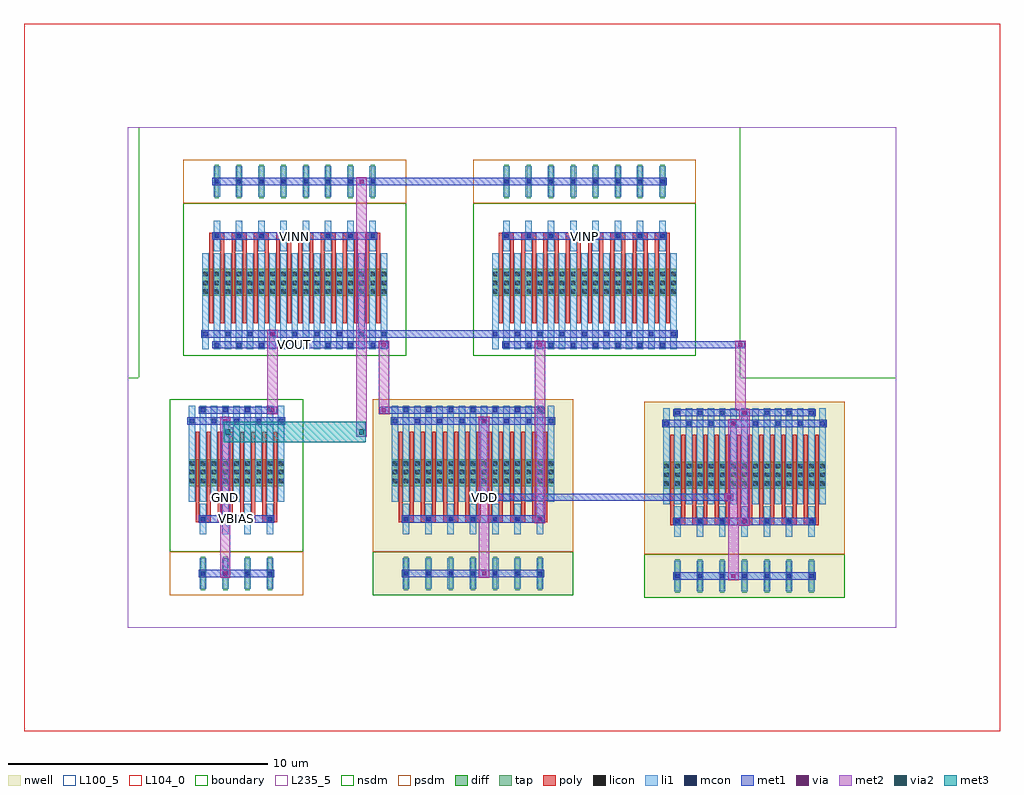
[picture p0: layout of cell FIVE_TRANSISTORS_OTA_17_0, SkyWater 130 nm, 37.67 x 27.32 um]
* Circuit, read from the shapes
.subckt FIVE_TRANSISTORS_OTA_17_0 GND VBIAS VDD VINN VINP VOUT
XM1 n1 VBIAS GND GND sky130_fd_pr__nfet_01v8 w=1.05 l=0.15 m=8
XM2 VOUT VINN n1 GND sky130_fd_pr__nfet_01v8 w=1.05 l=0.15 m=16
XM3 n2 VINP n1 GND sky130_fd_pr__nfet_01v8 w=1.05 l=0.15 m=16
XM4 VOUT n2 VDD VDD sky130_fd_pr__pfet_01v8 w=1.05 l=0.15 m=14
XM5 n2 n2 VDD VDD sky130_fd_pr__pfet_01v8 w=1.05 l=0.15 m=14
.ends

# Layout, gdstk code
from math import pi, radians
import gdstk
lib = gdstk.Library(unit=1e-6, precision=1e-09)
def R(c, l, rs):  # rectangles x0, y0, x1, y1
    for r in rs: c.add(gdstk.rectangle(r[:2], r[2:], *l))
def A(c, l, x, y, w, h, nx, ny, dx, dy):  # array of equal rectangles
    R(c, l, [(x+i*dx, y+j*dy, x+i*dx+w, y+j*dy+h) for i in range(nx) for j in range(ny)])
def P(c, l, *ps):  # polygons
    for p in ps: c.add(gdstk.Polygon(p, *l))
nwell = (64, 20)
diff = (65, 20)
tap = (65, 44)
poly = (66, 20)
licon = (66, 44)
li1 = (67, 20)
mcon = (67, 44)
met1 = (68, 20)
via = (68, 44)
met2 = (69, 20)
via2 = (69, 44)
met3 = (70, 20)
nsdm = (93, 44)
psdm = (94, 20)
L100_5 = (100, 5)
L104_0 = (104, 0)
boundary = (235, 4)
L235_5 = (235, 5)

dcl_pmos_s_28041393_x7_y = lib.new_cell('DCL_PMOS_S_28041393_X7_Y1_1746771636')
R(dcl_pmos_s_28041393_x7_y, nwell, [(1.99,0.94,9.73,8.5)])
R(dcl_pmos_s_28041393_x7_y, diff, [(2.725,3.25,8.995,4.3)])
A(dcl_pmos_s_28041393_x7_y, tap, 3.195, 7.015, 0.17, 1.29, 7, 1, 0.86, 0)
A(dcl_pmos_s_28041393_x7_y, poly, 2.99, 2.2, 0.15, 3.36, 14, 1, 0.43, 0)
A(dcl_pmos_s_28041393_x7_y, poly, 2.99, 5.425, 0.58, 0.27, 7, 1, 0.86, 0)
A(dcl_pmos_s_28041393_x7_y, licon, 2.765, 3.33, 0.17, 0.17, 3, 3, 0.43, 0.34)
A(dcl_pmos_s_28041393_x7_y, licon, 3.625, 3.33, 0.17, 0.17, 3, 3, 0.43, 0.34)
A(dcl_pmos_s_28041393_x7_y, licon, 4.485, 3.33, 0.17, 0.17, 3, 3, 0.43, 0.34)
A(dcl_pmos_s_28041393_x7_y, licon, 5.345, 3.33, 0.17, 0.17, 3, 3, 0.43, 0.34)
A(dcl_pmos_s_28041393_x7_y, licon, 6.205, 3.33, 0.17, 0.17, 3, 3, 0.43, 0.34)
A(dcl_pmos_s_28041393_x7_y, licon, 7.065, 3.33, 0.17, 0.17, 3, 3, 0.43, 0.34)
A(dcl_pmos_s_28041393_x7_y, licon, 7.925, 3.33, 0.17, 0.17, 3, 3, 0.43, 0.34)
A(dcl_pmos_s_28041393_x7_y, licon, 3.195, 5.475, 0.17, 0.17, 7, 2, 0.86, 2.1)
A(dcl_pmos_s_28041393_x7_y, li1, 2.725, 1.19, 0.25, 3.7, 15, 1, 0.43, 0)
A(dcl_pmos_s_28041393_x7_y, li1, 3.155, 4.97, 0.25, 1.18, 7, 2, 0.86, 2.1)
A(dcl_pmos_s_28041393_x7_y, mcon, 3.195, 1.275, 0.17, 0.17, 7, 2, 0.86, 4.2)
A(dcl_pmos_s_28041393_x7_y, mcon, 2.765, 1.695, 0.17, 0.17, 8, 1, 0.86, 0)
A(dcl_pmos_s_28041393_x7_y, mcon, 3.195, 7.575, 0.17, 0.17, 7, 1, 0.86, 0)
R(dcl_pmos_s_28041393_x7_y, met1, [(3.11,1.22,8.61,1.5), (2.68,1.64,9.04,1.92), (3.11,5.42,8.61,5.7), (3.11,7.52,8.61,7.8)])
R(dcl_pmos_s_28041393_x7_y, via, [(5.785,1.285,5.935,1.435), (6.215,1.705,6.365,1.855), (5.785,5.485,5.935,5.635), (6.215,7.585,6.365,7.735)])
R(dcl_pmos_s_28041393_x7_y, met2, [(5.66,1.2,6.06,5.72), (6.09,1.62,6.49,7.82)])
R(dcl_pmos_s_28041393_x7_y, nsdm, [(1.99,6.82,9.73,8.5)])
R(dcl_pmos_s_28041393_x7_y, psdm, [(1.99,0.94,9.73,6.82)])
R(dcl_pmos_s_28041393_x7_y, L100_5, [(0,0,10.75,9.66)])
R(dcl_pmos_s_28041393_x7_y, boundary, [(0,0,10.75,9.66)])

nmos_s_67517085_x4_y1_17 = lib.new_cell('NMOS_S_67517085_X4_Y1_1746771639')
R(nmos_s_67517085_x4_y1_17, diff, [(2.125,3.15,5.815,4.2)])
A(nmos_s_67517085_x4_y1_17, tap, 2.595, 6.915, 0.17, 1.29, 4, 1, 0.86, 0)
A(nmos_s_67517085_x4_y1_17, poly, 2.39, 2.1, 0.15, 3.36, 8, 1, 0.43, 0)
A(nmos_s_67517085_x4_y1_17, poly, 2.39, 5.325, 0.58, 0.27, 4, 1, 0.86, 0)
A(nmos_s_67517085_x4_y1_17, licon, 2.165, 3.23, 0.17, 0.17, 3, 3, 0.43, 0.34)
A(nmos_s_67517085_x4_y1_17, licon, 3.025, 3.23, 0.17, 0.17, 3, 3, 0.43, 0.34)
A(nmos_s_67517085_x4_y1_17, licon, 3.885, 3.23, 0.17, 0.17, 3, 3, 0.43, 0.34)
A(nmos_s_67517085_x4_y1_17, licon, 4.745, 3.23, 0.17, 0.17, 3, 3, 0.43, 0.34)
A(nmos_s_67517085_x4_y1_17, licon, 2.595, 5.375, 0.17, 0.17, 4, 2, 0.86, 2.1)
A(nmos_s_67517085_x4_y1_17, li1, 2.125, 1.09, 0.25, 3.7, 9, 1, 0.43, 0)
A(nmos_s_67517085_x4_y1_17, li1, 2.555, 4.87, 0.25, 1.18, 4, 2, 0.86, 2.1)
A(nmos_s_67517085_x4_y1_17, mcon, 2.595, 1.175, 0.17, 0.17, 4, 2, 0.86, 4.2)
A(nmos_s_67517085_x4_y1_17, mcon, 2.165, 1.595, 0.17, 0.17, 5, 1, 0.86, 0)
A(nmos_s_67517085_x4_y1_17, mcon, 2.595, 7.475, 0.17, 0.17, 4, 1, 0.86, 0)
R(nmos_s_67517085_x4_y1_17, met1, [(2.51,1.12,5.43,1.4), (2.08,1.54,5.86,1.82), (2.51,5.32,5.43,5.6), (2.51,7.42,5.43,7.7)])
R(nmos_s_67517085_x4_y1_17, via, [(4.325,1.605,4.475,1.755), (4.325,7.485,4.475,7.635)])
R(nmos_s_67517085_x4_y1_17, met2, [(4.2,1.52,4.6,7.72)])
R(nmos_s_67517085_x4_y1_17, nsdm, [(1.39,0.84,6.55,6.72)])
R(nmos_s_67517085_x4_y1_17, psdm, [(1.39,6.72,6.55,8.4)])
R(nmos_s_67517085_x4_y1_17, L100_5, [(0,0,8.17,9.66)])
R(nmos_s_67517085_x4_y1_17, boundary, [(0,0,8.17,9.66)])

pmos_s_48447827_x7_y1_17 = lib.new_cell('PMOS_S_48447827_X7_Y1_1746771640')
R(pmos_s_48447827_x7_y1_17, nwell, [(1.29,0.84,9.03,8.4)])
R(pmos_s_48447827_x7_y1_17, diff, [(2.025,3.15,8.295,4.2)])
A(pmos_s_48447827_x7_y1_17, tap, 2.495, 6.915, 0.17, 1.29, 7, 1, 0.86, 0)
A(pmos_s_48447827_x7_y1_17, poly, 2.29, 2.1, 0.15, 3.36, 14, 1, 0.43, 0)
A(pmos_s_48447827_x7_y1_17, poly, 2.29, 5.325, 0.58, 0.27, 7, 1, 0.86, 0)
A(pmos_s_48447827_x7_y1_17, licon, 2.065, 3.23, 0.17, 0.17, 3, 3, 0.43, 0.34)
A(pmos_s_48447827_x7_y1_17, licon, 2.925, 3.23, 0.17, 0.17, 3, 3, 0.43, 0.34)
A(pmos_s_48447827_x7_y1_17, licon, 3.785, 3.23, 0.17, 0.17, 3, 3, 0.43, 0.34)
A(pmos_s_48447827_x7_y1_17, licon, 4.645, 3.23, 0.17, 0.17, 3, 3, 0.43, 0.34)
A(pmos_s_48447827_x7_y1_17, licon, 5.505, 3.23, 0.17, 0.17, 3, 3, 0.43, 0.34)
A(pmos_s_48447827_x7_y1_17, licon, 6.365, 3.23, 0.17, 0.17, 3, 3, 0.43, 0.34)
A(pmos_s_48447827_x7_y1_17, licon, 7.225, 3.23, 0.17, 0.17, 3, 3, 0.43, 0.34)
A(pmos_s_48447827_x7_y1_17, licon, 2.495, 5.375, 0.17, 0.17, 7, 2, 0.86, 2.1)
A(pmos_s_48447827_x7_y1_17, li1, 2.025, 1.09, 0.25, 3.7, 15, 1, 0.43, 0)
A(pmos_s_48447827_x7_y1_17, li1, 2.455, 4.87, 0.25, 1.18, 7, 2, 0.86, 2.1)
A(pmos_s_48447827_x7_y1_17, mcon, 2.495, 1.175, 0.17, 0.17, 7, 2, 0.86, 4.2)
A(pmos_s_48447827_x7_y1_17, mcon, 2.065, 1.595, 0.17, 0.17, 8, 1, 0.86, 0)
A(pmos_s_48447827_x7_y1_17, mcon, 2.495, 7.475, 0.17, 0.17, 7, 1, 0.86, 0)
R(pmos_s_48447827_x7_y1_17, met1, [(2.41,1.12,7.91,1.4), (1.98,1.54,8.34,1.82), (2.41,5.32,7.91,5.6), (2.41,7.42,7.91,7.7)])
R(pmos_s_48447827_x7_y1_17, via, [(5.515,1.605,5.665,1.755), (5.515,7.485,5.665,7.635)])
R(pmos_s_48447827_x7_y1_17, met2, [(5.39,1.52,5.79,7.72)])
R(pmos_s_48447827_x7_y1_17, nsdm, [(1.29,6.72,9.03,8.4)])
R(pmos_s_48447827_x7_y1_17, psdm, [(1.29,0.84,9.03,6.72)])
R(pmos_s_48447827_x7_y1_17, L100_5, [(0,0,10.75,9.66)])
R(pmos_s_48447827_x7_y1_17, boundary, [(0,0,10.75,9.66)])

nmos_4t_16320549_x8_y1_1 = lib.new_cell('NMOS_4T_16320549_X8_Y1_1746771637')
R(nmos_4t_16320549_x8_y1_1, diff, [(2.025,3.15,9.155,4.2)])
A(nmos_4t_16320549_x8_y1_1, tap, 2.495, 6.915, 0.17, 1.29, 8, 1, 0.86, 0)
A(nmos_4t_16320549_x8_y1_1, poly, 2.29, 2.1, 0.15, 3.36, 16, 1, 0.43, 0)
A(nmos_4t_16320549_x8_y1_1, poly, 2.29, 5.325, 0.58, 0.27, 8, 1, 0.86, 0)
A(nmos_4t_16320549_x8_y1_1, licon, 2.065, 3.23, 0.17, 0.17, 3, 3, 0.43, 0.34)
A(nmos_4t_16320549_x8_y1_1, licon, 2.925, 3.23, 0.17, 0.17, 3, 3, 0.43, 0.34)
A(nmos_4t_16320549_x8_y1_1, licon, 3.785, 3.23, 0.17, 0.17, 3, 3, 0.43, 0.34)
A(nmos_4t_16320549_x8_y1_1, licon, 4.645, 3.23, 0.17, 0.17, 3, 3, 0.43, 0.34)
A(nmos_4t_16320549_x8_y1_1, licon, 5.505, 3.23, 0.17, 0.17, 3, 3, 0.43, 0.34)
A(nmos_4t_16320549_x8_y1_1, licon, 6.365, 3.23, 0.17, 0.17, 3, 3, 0.43, 0.34)
A(nmos_4t_16320549_x8_y1_1, licon, 7.225, 3.23, 0.17, 0.17, 3, 3, 0.43, 0.34)
A(nmos_4t_16320549_x8_y1_1, licon, 8.085, 3.23, 0.17, 0.17, 3, 3, 0.43, 0.34)
A(nmos_4t_16320549_x8_y1_1, licon, 2.495, 5.375, 0.17, 0.17, 8, 2, 0.86, 2.1)
A(nmos_4t_16320549_x8_y1_1, li1, 2.025, 1.09, 0.25, 3.7, 17, 1, 0.43, 0)
A(nmos_4t_16320549_x8_y1_1, li1, 2.455, 4.87, 0.25, 1.18, 8, 2, 0.86, 2.1)
A(nmos_4t_16320549_x8_y1_1, mcon, 2.495, 1.175, 0.17, 0.17, 8, 2, 0.86, 4.2)
A(nmos_4t_16320549_x8_y1_1, mcon, 2.065, 1.595, 0.17, 0.17, 9, 1, 0.86, 0)
A(nmos_4t_16320549_x8_y1_1, mcon, 2.495, 7.475, 0.17, 0.17, 8, 1, 0.86, 0)
R(nmos_4t_16320549_x8_y1_1, met1, [(2.41,1.12,8.77,1.4), (1.98,1.54,9.2,1.82), (2.41,5.32,8.77,5.6), (2.41,7.42,8.77,7.7)])
R(nmos_4t_16320549_x8_y1_1, nsdm, [(1.29,0.84,9.89,6.72)])
R(nmos_4t_16320549_x8_y1_1, psdm, [(1.29,6.72,9.89,8.4)])
R(nmos_4t_16320549_x8_y1_1, L100_5, [(0,0,11.61,9.66)])
R(nmos_4t_16320549_x8_y1_1, boundary, [(0,0,11.61,9.66)])

nmos_4t_2405365_x8_y1_17 = lib.new_cell('NMOS_4T_2405365_X8_Y1_1746771638')
R(nmos_4t_2405365_x8_y1_17, diff, [(2.025,3.15,9.155,4.2)])
A(nmos_4t_2405365_x8_y1_17, tap, 2.495, 6.915, 0.17, 1.29, 8, 1, 0.86, 0)
A(nmos_4t_2405365_x8_y1_17, poly, 2.29, 2.1, 0.15, 3.36, 16, 1, 0.43, 0)
A(nmos_4t_2405365_x8_y1_17, poly, 2.29, 5.325, 0.58, 0.27, 8, 1, 0.86, 0)
A(nmos_4t_2405365_x8_y1_17, licon, 2.065, 3.23, 0.17, 0.17, 3, 3, 0.43, 0.34)
A(nmos_4t_2405365_x8_y1_17, licon, 2.925, 3.23, 0.17, 0.17, 3, 3, 0.43, 0.34)
A(nmos_4t_2405365_x8_y1_17, licon, 3.785, 3.23, 0.17, 0.17, 3, 3, 0.43, 0.34)
A(nmos_4t_2405365_x8_y1_17, licon, 4.645, 3.23, 0.17, 0.17, 3, 3, 0.43, 0.34)
A(nmos_4t_2405365_x8_y1_17, licon, 5.505, 3.23, 0.17, 0.17, 3, 3, 0.43, 0.34)
A(nmos_4t_2405365_x8_y1_17, licon, 6.365, 3.23, 0.17, 0.17, 3, 3, 0.43, 0.34)
A(nmos_4t_2405365_x8_y1_17, licon, 7.225, 3.23, 0.17, 0.17, 3, 3, 0.43, 0.34)
A(nmos_4t_2405365_x8_y1_17, licon, 8.085, 3.23, 0.17, 0.17, 3, 3, 0.43, 0.34)
A(nmos_4t_2405365_x8_y1_17, licon, 2.495, 5.375, 0.17, 0.17, 8, 2, 0.86, 2.1)
A(nmos_4t_2405365_x8_y1_17, li1, 2.025, 1.09, 0.25, 3.7, 17, 1, 0.43, 0)
A(nmos_4t_2405365_x8_y1_17, li1, 2.455, 4.87, 0.25, 1.18, 8, 2, 0.86, 2.1)
A(nmos_4t_2405365_x8_y1_17, mcon, 2.495, 1.175, 0.17, 0.17, 8, 2, 0.86, 4.2)
A(nmos_4t_2405365_x8_y1_17, mcon, 2.065, 1.595, 0.17, 0.17, 9, 1, 0.86, 0)
A(nmos_4t_2405365_x8_y1_17, mcon, 2.495, 7.475, 0.17, 0.17, 8, 1, 0.86, 0)
R(nmos_4t_2405365_x8_y1_17, met1, [(2.41,1.12,8.77,1.4), (1.98,1.54,9.2,1.82), (2.41,5.32,8.77,5.6), (2.41,7.42,8.77,7.7)])
R(nmos_4t_2405365_x8_y1_17, nsdm, [(1.29,0.84,9.89,6.72)])
R(nmos_4t_2405365_x8_y1_17, psdm, [(1.29,6.72,9.89,8.4)])
R(nmos_4t_2405365_x8_y1_17, L100_5, [(0,0,11.61,9.66)])
R(nmos_4t_2405365_x8_y1_17, boundary, [(0,0,11.61,9.66)])

five_transistors_ota_17_ = lib.new_cell('FIVE_TRANSISTORS_OTA_17_0')
R(five_transistors_ota_17_, met1, [(15.75,4.06,16.07,4.34), (15.75,4.06,16.07,4.34), (15.75,4.06,16.07,4.34), (15.75,4.06,16.07,4.34), (13.6,4.9,13.92,5.18), (13.6,4.9,13.92,5.18), (13.76,4.9,23.22,5.18), (23.06,4.9,23.38,5.18), (23.06,4.9,23.38,5.18), (5.43,8.26,5.75,8.54), (5.43,8.26,5.75,8.54), (5.43,8.26,5.75,8.54), (5.43,8.26,5.75,8.54), (9.73,8.26,10.05,8.54), (9.73,8.26,10.05,8.54), (9.89,8.26,10.75,8.54), (9.46,10.78,9.89,11.06), (9.73,10.78,10.05,11.06), (9.73,10.78,10.05,11.06), (15.75,10.78,16.07,11.06), (15.75,10.78,16.07,11.06), (15.75,10.78,16.07,11.06), (15.75,10.78,16.07,11.06), (20.64,10.78,23.65,11.06), (23.49,10.78,23.81,11.06), (23.49,10.78,23.81,11.06), (5.43,11.2,5.75,11.48), (5.43,11.2,5.75,11.48), (5.43,11.2,5.75,11.48), (5.43,11.2,5.75,11.48), (9.89,11.2,14.19,11.48), (8.87,17.08,9.19,17.36), (8.87,17.08,9.19,17.36), (8.87,17.08,9.19,17.36), (8.87,17.08,9.19,17.36), (9.46,17.08,14.62,17.36)])
P(five_transistors_ota_17_, met1, [(0,0),(0,0),(0,0),(0,0)],
  [(0,0),(0,0),(0,0),(0,0)],
  [(0,0),(0,0),(0,0),(0,0)],
  [(0,0),(0,0),(0,0),(0,0)],
  [(0,0),(0,0),(0,0),(0,0)],
  [(0,0),(0,0),(0,0),(0,0)],
  [(0,0),(0,0),(0,0),(0,0)],
  [(0,0),(0,0),(0,0),(0,0)],
  [(0,0),(0,0),(0,0),(0,0)],
  [(0,0),(0,0),(0,0),(0,0)],
  [(0,0),(0,0),(0,0),(0,0)],
  [(0,0),(0,0),(0,0),(0,0)],
  [(0,0),(0,0),(0,0),(0,0)],
  [(0,0),(0,0),(0,0),(0,0)],
  [(0,0),(0,0),(0,0),(0,0)],
  [(0,0),(0,0),(0,0),(0,0)])
R(five_transistors_ota_17_, via, [(15.835,4.125,15.985,4.275), (15.835,4.125,15.985,4.275), (15.835,4.125,15.985,4.275), (15.835,4.125,15.985,4.275), (13.685,4.965,13.835,5.115), (13.685,4.965,13.835,5.115), (23.145,4.965,23.295,5.115), (23.145,4.965,23.295,5.115), (5.515,8.325,5.665,8.475), (5.515,8.325,5.665,8.475), (5.515,8.325,5.665,8.475), (5.515,8.325,5.665,8.475), (9.815,8.325,9.965,8.475), (9.815,8.325,9.965,8.475), (9.815,10.845,9.965,10.995), (9.815,10.845,9.965,10.995), (15.835,10.845,15.985,10.995), (15.835,10.845,15.985,10.995), (15.835,10.845,15.985,10.995), (15.835,10.845,15.985,10.995), (23.575,10.845,23.725,10.995), (23.575,10.845,23.725,10.995), (5.515,11.265,5.665,11.415), (5.515,11.265,5.665,11.415), (5.515,11.265,5.665,11.415), (5.515,11.265,5.665,11.415), (8.955,17.145,9.105,17.295), (8.955,17.145,9.105,17.295), (8.955,17.145,9.105,17.295), (8.955,17.145,9.105,17.295)])
R(five_transistors_ota_17_, met2, [(15.71,4.04,16.11,4.36), (15.71,4.04,16.11,4.36), (15.71,4.04,16.11,4.36), (15.71,4.04,16.11,4.36), (15.71,4.2,16.11,10.92), (13.56,4.88,13.96,5.2), (13.56,4.88,13.96,5.2), (23.02,4.88,23.42,5.2), (23.02,4.88,23.42,5.2), (3.67,7.375,4.07,7.745), (3.67,7.375,4.07,7.745), (3.67,7.375,4.07,7.745), (3.67,7.375,4.07,7.745), (8.83,7.375,9.23,7.745), (8.83,7.375,9.23,7.745), (8.83,7.375,9.23,7.745), (8.83,7.375,9.23,7.745), (8.83,7.56,9.23,17.22), (5.39,8.24,5.79,8.56), (5.39,8.24,5.79,8.56), (5.39,8.24,5.79,8.56), (5.39,8.24,5.79,8.56), (9.69,8.24,10.09,8.56), (9.69,8.24,10.09,8.56), (5.39,8.4,5.79,11.34), (9.69,8.4,10.09,10.92), (23.45,8.4,23.85,10.92), (9.69,10.76,10.09,11.08), (9.69,10.76,10.09,11.08), (15.71,10.76,16.11,11.08), (15.71,10.76,16.11,11.08), (15.71,10.76,16.11,11.08), (15.71,10.76,16.11,11.08), (23.45,10.76,23.85,11.08), (23.45,10.76,23.85,11.08), (5.39,11.18,5.79,11.5), (5.39,11.18,5.79,11.5), (5.39,11.18,5.79,11.5), (5.39,11.18,5.79,11.5), (8.83,17.06,9.23,17.38), (8.83,17.06,9.23,17.38), (8.83,17.06,9.23,17.38), (8.83,17.06,9.23,17.38)])
P(five_transistors_ota_17_, met2, [(0,0),(0,0),(0,0),(0,0)],
  [(0,0),(0,0),(0,0),(0,0)],
  [(0,0),(0,0),(0,0),(0,0)],
  [(0,0),(0,0),(0,0),(0,0)],
  [(0,0),(0,0),(0,0),(0,0)],
  [(0,0),(0,0),(0,0),(0,0)])
R(five_transistors_ota_17_, via2, [(3.77,7.46,3.97,7.66), (3.77,7.46,3.97,7.66), (3.77,7.46,3.97,7.66), (3.77,7.46,3.97,7.66), (8.93,7.46,9.13,7.66), (8.93,7.46,9.13,7.66), (8.93,7.46,9.13,7.66), (8.93,7.46,9.13,7.66)])
R(five_transistors_ota_17_, met3, [(3.705,7.16,4.035,7.96), (3.705,7.16,4.035,7.96), (3.705,7.16,4.035,7.96), (3.705,7.16,4.035,7.96), (3.87,7.16,9.03,7.96), (8.865,7.16,9.195,7.96), (8.865,7.16,9.195,7.96), (8.865,7.16,9.195,7.96), (8.865,7.16,9.195,7.96)])
R(five_transistors_ota_17_, L104_0, [(-4,-4,33.67,23.32)])
R(five_transistors_ota_17_, L235_5, [(0,0,29.67,19.32)])
five_transistors_ota_17_.add(gdstk.Reference(dcl_pmos_s_28041393_x7_y, (29.67,9.66), rotation=pi))
five_transistors_ota_17_.add(gdstk.Reference(nmos_s_67517085_x4_y1_17, (8.17,9.66), rotation=pi))
five_transistors_ota_17_.add(gdstk.Reference(pmos_s_48447827_x7_y1_17, (8.17,9.66), x_reflection=True))
five_transistors_ota_17_.add(gdstk.Reference(nmos_4t_16320549_x8_y1_1, (12.04,9.66), rotation=pi, x_reflection=True))
five_transistors_ota_17_.add(gdstk.Reference(nmos_4t_2405365_x8_y1_17, (12.04,9.66)))
five_transistors_ota_17_.add(gdstk.Label('VDD', (13.76,5.04), layer=69, texttype=5))
five_transistors_ota_17_.add(gdstk.Label('VBIAS', (4.2,4.2), layer=68, texttype=5))
five_transistors_ota_17_.add(gdstk.Label('GND', (3.77,5.04), layer=69, texttype=5))
five_transistors_ota_17_.add(gdstk.Label('VOUT', (6.45,10.92), layer=68, texttype=5))
five_transistors_ota_17_.add(gdstk.Label('VINN', (6.45,15.12), layer=68, texttype=5))
five_transistors_ota_17_.add(gdstk.Label('VINP', (17.63,15.12), layer=68, texttype=5))

lib.write_gds('FIVE_TRANSISTORS_OTA_17_0.gds')
